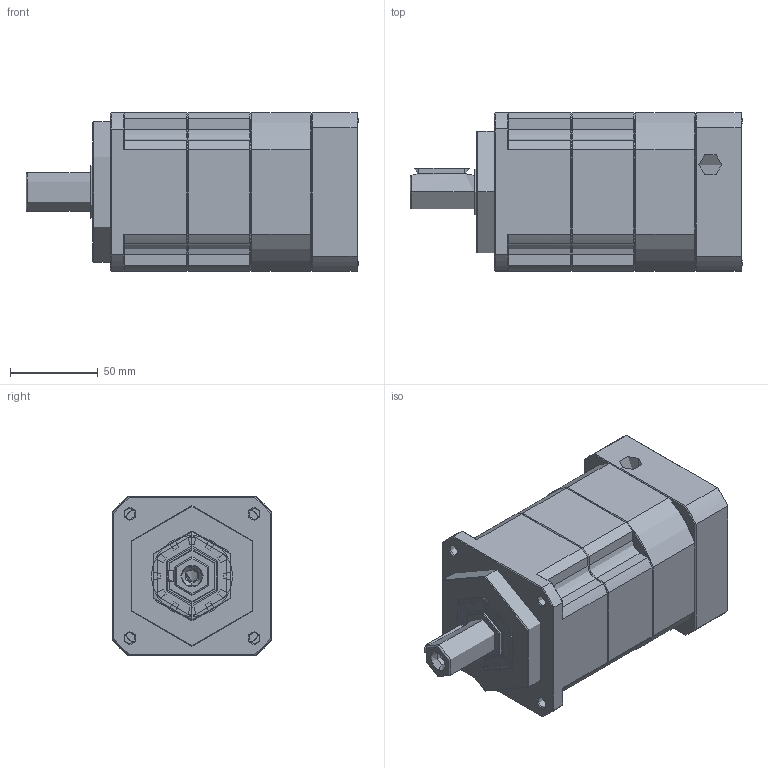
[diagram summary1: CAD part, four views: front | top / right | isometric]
STEP (ISO 10303-21) file: header records copied from the file, then geometry measured from it (millimetres).
FILE_DESCRIPTION (( 'STEP AP214' ), '1' );
FILE_NAME ('ZPB090-D22-L2-P1-19-80-100-M6.step', '2024-06-07T18:21:07', ( 'Windows 蚚誧' ), ( 'Organization' ), 'SwSTEP 2.0', 'SolidWorks 2016', '' );
FILE_SCHEMA (( 'AUTOMOTIVE_DESIGN' ));
Length unit declared in the file: millimetre
Products named in the file (1): ZPB090-D22-L2-P1-19-80-100-M6
Bounding box: 189 x 90 x 90 mm (x, y, z)
Topology: 0 solids, 34 shells, 1897 faces, 5032 edges, 3189 vertices
Faces by surface type: plane 972, bspline 388, cone 291, cylinder 244, torus 2
Full cylindrical faces by diameter (mm): 6.72 x4
Entity records: 96757 total; most frequent: CARTESIAN_POINT 48367, ORIENTED_EDGE 9920, DIRECTION 7704, EDGE_CURVE 4981, VECTOR 3276, LINE 3276, VERTEX_POINT 3158, AXIS2_PLACEMENT_3D 2214
One B-rep face of a CAD part: STEP entity #14502.
In plain terms, the planar face has unit normal (-1, 0, 0).
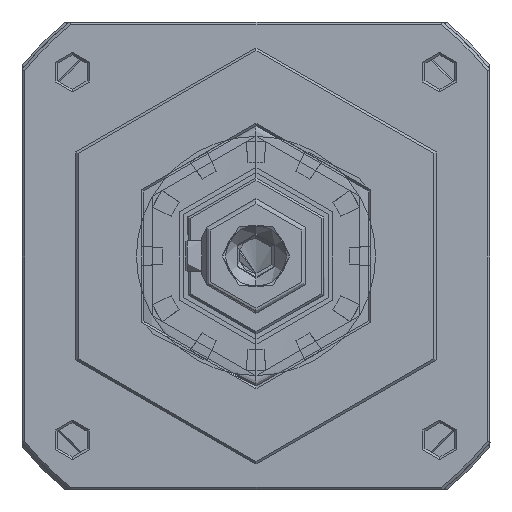
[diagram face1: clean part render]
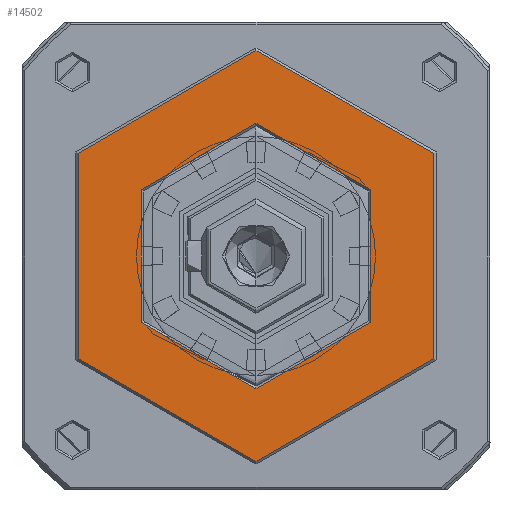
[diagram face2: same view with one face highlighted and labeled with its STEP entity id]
Its self-contained STEP definition (entity closure, numbers rounded to 3 decimals):
#107 = CARTESIAN_POINT ( 'NONE',  ( 0., -39.974, 39.974 ) ) ;
#7010 = CARTESIAN_POINT ( 'NONE',  ( 0., 0., 25.5 ) ) ;
#7255 = EDGE_CURVE ( 'NONE', #51440, #35245, #80984, .T. ) ;
#7354 = PLANE ( 'NONE',  #42203 ) ;
#8889 = CARTESIAN_POINT ( 'NONE',  ( 0., 0., -39.5 ) ) ;
#9935 = CIRCLE ( 'NONE', #76234, 39.5 ) ;
#10268 = CARTESIAN_POINT ( 'NONE',  ( 0., 0., -25.5 ) ) ;
#11273 = ORIENTED_EDGE ( 'NONE', *, *, #11698, .F. ) ;
#11698 = EDGE_CURVE ( 'NONE', #12767, #96389, #66033, .T. ) ;
#12767 = VERTEX_POINT ( 'NONE', #50831 ) ;
#14502 = ADVANCED_FACE ( 'NONE', ( #49161, #33716 ), #7354, .F. ) ;
#15598 = EDGE_CURVE ( 'NONE', #35245, #51440, #37030, .T. ) ;
#16255 = CARTESIAN_POINT ( 'NONE',  ( 0., 0., 0. ) ) ;
#20933 = DIRECTION ( 'NONE',  ( 1., 0., 0. ) ) ;
#23871 = EDGE_CURVE ( 'NONE', #96389, #12767, #9935, .T. ) ;
#23914 = DIRECTION ( 'NONE',  ( 1., 0., 0. ) ) ;
#33088 = DIRECTION ( 'NONE',  ( 0., 0., 1. ) ) ;
#33716 = FACE_OUTER_BOUND ( 'NONE', #50709, .T. ) ;
#35076 = AXIS2_PLACEMENT_3D ( 'NONE', #44127, #20933, #80850 ) ;
#35245 = VERTEX_POINT ( 'NONE', #10268 ) ;
#37030 = CIRCLE ( 'NONE', #41622, 25.5 ) ;
#38778 = DIRECTION ( 'NONE',  ( 0., 0., -1. ) ) ;
#39499 = ORIENTED_EDGE ( 'NONE', *, *, #7255, .T. ) ;
#39754 = DIRECTION ( 'NONE',  ( 1., 0., 0. ) ) ;
#41622 = AXIS2_PLACEMENT_3D ( 'NONE', #79434, #78443, #33088 ) ;
#42203 = AXIS2_PLACEMENT_3D ( 'NONE', #107, #23914, #38778 ) ;
#44066 = ORIENTED_EDGE ( 'NONE', *, *, #23871, .F. ) ;
#44127 = CARTESIAN_POINT ( 'NONE',  ( 0., 0., 0. ) ) ;
#47072 = DIRECTION ( 'NONE',  ( 0., 0., -1. ) ) ;
#49161 = FACE_BOUND ( 'NONE', #95511, .T. ) ;
#50709 = EDGE_LOOP ( 'NONE', ( #44066, #11273 ) ) ;
#50831 = CARTESIAN_POINT ( 'NONE',  ( 0., 0., 39.5 ) ) ;
#51440 = VERTEX_POINT ( 'NONE', #7010 ) ;
#54373 = CARTESIAN_POINT ( 'NONE',  ( 0., 0., 0. ) ) ;
#61640 = ORIENTED_EDGE ( 'NONE', *, *, #15598, .T. ) ;
#63334 = AXIS2_PLACEMENT_3D ( 'NONE', #16255, #78448, #77153 ) ;
#66033 = CIRCLE ( 'NONE', #35076, 39.5 ) ;
#76234 = AXIS2_PLACEMENT_3D ( 'NONE', #54373, #39754, #47072 ) ;
#77153 = DIRECTION ( 'NONE',  ( 0., 0., 1. ) ) ;
#78443 = DIRECTION ( 'NONE',  ( 1., 0., 0. ) ) ;
#78448 = DIRECTION ( 'NONE',  ( 1., 0., 0. ) ) ;
#79434 = CARTESIAN_POINT ( 'NONE',  ( 0., 0., 0. ) ) ;
#80850 = DIRECTION ( 'NONE',  ( 0., 0., -1. ) ) ;
#80984 = CIRCLE ( 'NONE', #63334, 25.5 ) ;
#95511 = EDGE_LOOP ( 'NONE', ( #39499, #61640 ) ) ;
#96389 = VERTEX_POINT ( 'NONE', #8889 ) ;
